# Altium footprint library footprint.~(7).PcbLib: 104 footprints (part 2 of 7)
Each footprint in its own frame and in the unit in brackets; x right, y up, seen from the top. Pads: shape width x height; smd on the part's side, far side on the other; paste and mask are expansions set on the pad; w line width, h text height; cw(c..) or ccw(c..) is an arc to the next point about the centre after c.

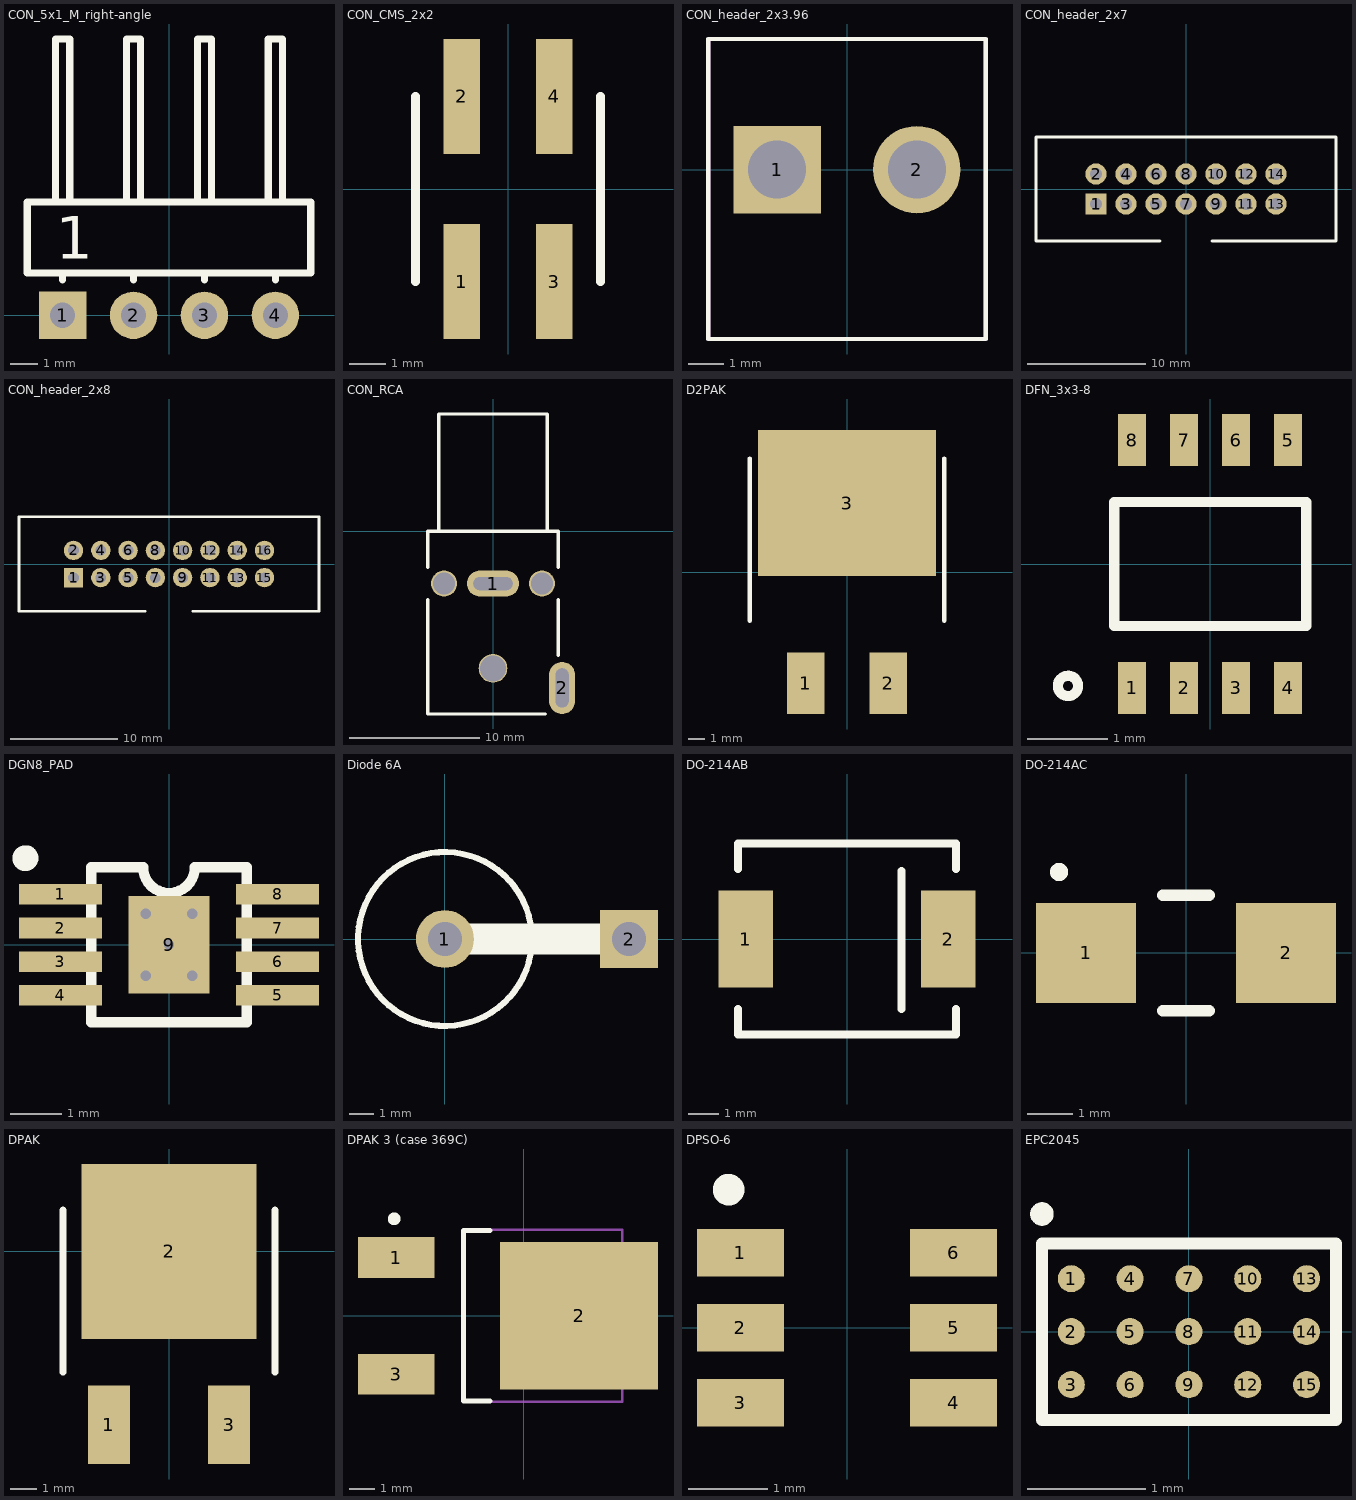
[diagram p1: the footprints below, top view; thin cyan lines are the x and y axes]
## CON_5x1_M_right-angle [mm] "step 2.54 TSW-104-22-G-S-RA"
height 2.41
pads (4):
  rect 1.7x1.7 hole 0.9: 1(-3.81,0)
  round 1.7 hole 0.9: 2(-1.27,0) 3(1.27,0) 4(3.81,0)
Top Overlay:
  lines w0.254: -4.064,4.06 -4.064,9.9 -3.556,9.9 -3.556,4.06 ; -3.81,1.27 -3.81,1.52 ; -1.524,4.06 -1.524,9.9 -1.016,9.9 -1.016,4.06 ; -1.27,1.27 -1.27,1.52 ; 1.016,4.06 1.016,9.9 1.524,9.9 1.524,4.06 ; 1.27,1.27 1.27,1.52 ; 3.556,4.06 3.556,9.9 4.064,9.9 4.064,4.06 ; 3.81,1.27 3.81,1.52 ; -5.08,1.52 5.08,1.52 5.08,4.06 -5.08,4.06 -5.08,1.52
  text "1" at -4.064,2.032 h1.52
3D body: height 2.41, standoff 0, extent -5.08,1.524 5.08,4.06
3D body: height 1.47, standoff 1.07, extent -4.191,-0.254 -3.429,9.906
3D body: height 1.47, standoff 1.07, extent -1.651,-0.254 -0.889,9.906
3D body: height 1.47, standoff 1.07, extent 0.889,-0.254 1.651,9.906
3D body: height 1.47, standoff 1.07, extent 3.429,-0.254 4.191,9.906

## CON_CMS_2x2 [mm] "2x2x2.54mm CMS"
height 9
pads (4):
  rect 1x3.15 smd: 1(-1.27,-2.54) 2(-1.27,2.54) 3(1.27,-2.54) 4(1.27,2.54)
Top Overlay:
  lines w0.254: -2.54,-2.54 -2.54,2.54 ; 2.54,-2.54 2.54,2.54
3D body: height 9.93, standoff 4.13, extent -1.59,0.95 -0.95,1.59
3D body: height 9.93, standoff 4.13, extent 0.95,0.95 1.59,1.59
3D body: height 9.93, standoff 4.13, extent 0.95,-1.59 1.59,-0.95
3D body: height 9.93, standoff 4.13, extent -1.59,-1.59 -0.95,-0.95
3D body: height 4.13, standoff 1.59, extent -2.54,-2.54 2.54,2.54

## CON_header_2x3.96 [mm] "2x3.96mm with lock"
height 10.7
pads (2):
  rect 2.475x2.475 hole 1.65: 1(-1.98,0)
  round 2.475 hole 1.65: 2(1.98,0)
Top Overlay:
  lines w0.127: -3.93,-4.8 -3.93,3.7 3.93,3.7 3.93,-4.8 -3.93,-4.8
Mechanical 4:
  lines w0.127: -3.93,-4.8 -3.93,3.7 ; -3.93,-4.8 3.93,-4.8 ; -3.93,-4.8 -3.93,3.7 ; -3.93,-4.8 3.93,-4.8 ; -3.93,3.7 3.93,3.7 ; -3.93,3.7 3.93,3.7 ; 3.93,-4.8 3.93,3.7 ; 3.93,-4.8 3.93,3.7
3D body: height 10.7, standoff 0, extent -3.93,-4.8 3.93,3.7

## CON_header_2x7 [mm] "2x7x2.54mm with lock"
height 9
pads (14):
  rect 1.8x1.8 hole 1: 1(-7.62,-1.27)
  round 1.8 hole 1: 2(-7.62,1.27) 3(-5.08,-1.27) 4(-5.08,1.27) 5(-2.54,-1.27) 6(-2.54,1.27) 7(0,-1.27) 8(0,1.27) 9(2.54,-1.27) 10(2.54,1.27) 11(5.08,-1.27) 12(5.08,1.27) 13(7.62,-1.27) 14(7.62,1.27)
Top Overlay:
  lines w0.254: -2.2,-4.4 -12.7,-4.4 -12.7,4.4 12.7,4.4 12.7,-4.4 2.2,-4.4
3D body: height 9, standoff 0, extent -12.7,-4.4 12.7,4.4

## CON_header_2x8 [mm] "2x8x2.54mm with lock"
height 9
pads (16):
  rect 1.8x1.8 hole 1: 1(-8.89,-1.27)
  round 1.8 hole 1: 2(-8.89,1.27) 3(-6.35,-1.27) 4(-6.35,1.27) 5(-3.81,-1.27) 6(-3.81,1.27) 7(-1.27,-1.27) 8(-1.27,1.27) 9(1.27,-1.27) 10(1.27,1.27) 11(3.81,-1.27) 12(3.81,1.27) 13(6.35,-1.27) 14(6.35,1.27) 15(8.89,-1.27) 16(8.89,1.27)
Top Overlay:
  lines w0.254: -2.2,-4.4 -13.97,-4.4 -13.97,4.4 13.97,4.4 13.97,-4.4 2.2,-4.4
3D body: height 9, standoff 0, extent -13.97,-4.4 13.97,4.4

## CON_RCA [mm] "JEITA RC-5231"
height 13
pads (5):
  oval 4x2 hole 1 slot 3 at 0 deg: 1(0,-4)
  oval 2x4 hole 1 slot 3 at 90 deg: 2(5.3,-12)
  round 2 hole 1.7: ""(-3.75,-4) ""(3.75,-4)
  round 2.2 hole 2: ""(0,-10.5)
Top Overlay:
  lines w0.254: -5,-5.25 -5,-14 4,-14 ; -5,-2.75 -5,0 5,0 5,-2.75 ; -4.15,0 -4.15,9 4.15,9 4.15,0 ; 5,-9.5 5,-5.25
3D body: height 13, standoff 0, extent -5,-14 5,0
3D body: height 10.65, standoff 2.35, extent -4.15,0 4.15,9

## D2PAK [mm] "D2PAK"
height 4.5
pads (3):
  rect 2.3x3.8 smd: 1(-2.54,-6.85) 2(2.54,-6.85)
  rect 11x9 smd: 3(0,4.25)
Top Overlay:
  lines w0.254: -6,-3 -6,7 ; 6,-3 6,7
3D body: height 2.38, standoff 0, extent -5.25,-3 5.25,7

## DFN_3x3-8 [mm] "DFN 3x3x0.9 - 8pin - 0.65pitch"
height 0.9
pads (8):
  rect 0.35x0.65 smd: 1(-0.975,-1.55) 2(-0.325,-1.55) 3(0.325,-1.55) 4(0.975,-1.55) 5(0.975,1.55) 6(0.325,1.55) 7(-0.325,1.55) 8(-0.975,1.55)
Top Overlay:
  circle w0.127: c-1.778,-1.524 r0.127
  lines w0.127: -1.2,-0.775 1.2,-0.775 1.2,0.775 -1.2,0.775 -1.2,-0.775
3D body: height 0.9, standoff 0, extent -1.5,-1.5 1.5,1.5

## DGN8_PAD [mm] "MSOP-PowerPAD; 8 Leads; Pitch 0.65 mm"
height 1.1
pads (9):
  rect 1.6x0.4 smd: 1(-2.1,0.975) 2(-2.1,0.325) 3(-2.1,-0.325) 4(-2.1,-0.975) 5(2.1,-0.975) 6(2.1,-0.325) 7(2.1,0.325) 8(2.1,0.975)
  rect 1.57x1.89 smd: 9(0,0)
via 0,0 diameter 0.4 hole 0.2
via -0.45,0.6 diameter 0.4 hole 0.2
via 0.45,0.6 diameter 0.4 hole 0.2
via 0.45,-0.6 diameter 0.4 hole 0.2
via -0.45,-0.6 diameter 0.4 hole 0.2
Top Overlay:
  circle w0.25: c-2.775,1.675 r0.125
  lines w0.2: -0.517,1.5 -1.5,1.5 -1.5,-1.5 1.5,-1.5 1.5,1.5 0.517,1.5 ; -0.5,1.5 ccw(c0,1.5) 0.5,1.5

## Diode 6A [mm] "diode 6A"
height 10
pads (2):
  round 2.4 hole 1.4: 1(0,0)
  rect 2.4x2.4 hole 1.4: 2(7.62,0)
Top Overlay:
  circle w0.254: c0,0 r3.6
  lines w1.3: 0,0 7.62,0

## DO-214AB [mil]
height 103.15
pads (2):
  rect 70x125 smd: 1(-130,0) 2(130,0)
Top Overlay:
  lines w10: -139.96,-90 -139.96,-122.44 139.96,-122.44 139.96,-90 ; -139.96,90 -139.96,122.44 139.96,122.44 139.96,90 ; 70,-90 70,87.17
3D body: height 103.15, standoff 0, extent -139.96,-122.44 139.96,122.44

## DO-214AC [mm]
height 2.3
pads (2):
  rect 2.2x2.2 smd: 1(-2.2,0) 2(2.2,0)
Top Overlay:
  circle w0.2: c-2.794,1.778 r0.1
  lines w0.254: -0.508,-1.27 0.508,-1.27 ; -0.508,1.27 0.508,1.27
3D body: height 2.3, standoff 0, extent -2.75,-1.4 2.75,1.4

## DPAK [mm] "DPAK"
height 2.38
pads (3):
  rect 1.6x3 smd: 1(-2.3,-6.65) 3(2.3,-6.65)
  rect 6.7x6.7 smd: 2(0,0)
Top Overlay:
  lines w0.254: -4.064,-4.634 -4.064,1.586 ; 4.064,-4.634 4.064,1.586
3D body: height 2.38, standoff 0, extent -3.365,-4.634 3.365,1.586

## DPAK 3 (case 369C) [mm] "D-PAK, 3-Pads, Body 6,21x6,73mm (max), IPC Medium Density"
height 2.38
pads (3):
  rect 3x1.6 smd: 1(-5,2.29) 3(-5,-2.29)
  rect 6.2x5.8 smd: 2(2.18,0)
Top Overlay:
  circle w0.25: c-5.08,3.81 r0.125
  lines w0.2: -1.32,-3.35 -2.35,-3.35 -2.35,3.35 -1.32,3.35
Mechanical 13:
  lines w0.1: -2.35,-3.375 3.87,-3.375 3.87,3.375 -2.35,3.375 -2.35,-3.375
3D body: height 2.38, standoff 0, extent -2.35,-3.375 3.87,3.375

## DPSO-6 [mm]
height 1.1
pads (6):
  rect 1.1x0.6 smd: 1(-1.35,0.95) 2(-1.35,0) 3(-1.35,-0.95) 4(1.35,-0.95) 5(1.35,0) 6(1.35,0.95)
Top Overlay:
  circle w0.2: c-1.5,1.75 r0.1
3D body: height 1.1, standoff 0, extent -0.9,-1.5 0.9,1.5

## EPC2045 [mm] "EPC2045 GaNFet"
height 0.685
pads (15):
  round 0.23 smd: 1(-1,0.45) 2(-1,0) 3(-1,-0.45) 4(-0.5,0.45) 5(-0.5,0) 6(-0.5,-0.45) 7(0,0.45) 8(0,0) 9(0,-0.45) 10(0.5,0.45) 11(0.5,0) 12(0.5,-0.45) 13(1,0.45) 14(1,0) 15(1,-0.45)
Top Overlay:
  circle w0.1: c-1.25,1 r0.05
  lines w0.1: -1.25,-0.75 -1.25,0.75 1.25,0.75 1.25,-0.75 -1.25,-0.75
3D body: height 0.68, standoff 0, extent -1.25,-0.75 1.25,0.75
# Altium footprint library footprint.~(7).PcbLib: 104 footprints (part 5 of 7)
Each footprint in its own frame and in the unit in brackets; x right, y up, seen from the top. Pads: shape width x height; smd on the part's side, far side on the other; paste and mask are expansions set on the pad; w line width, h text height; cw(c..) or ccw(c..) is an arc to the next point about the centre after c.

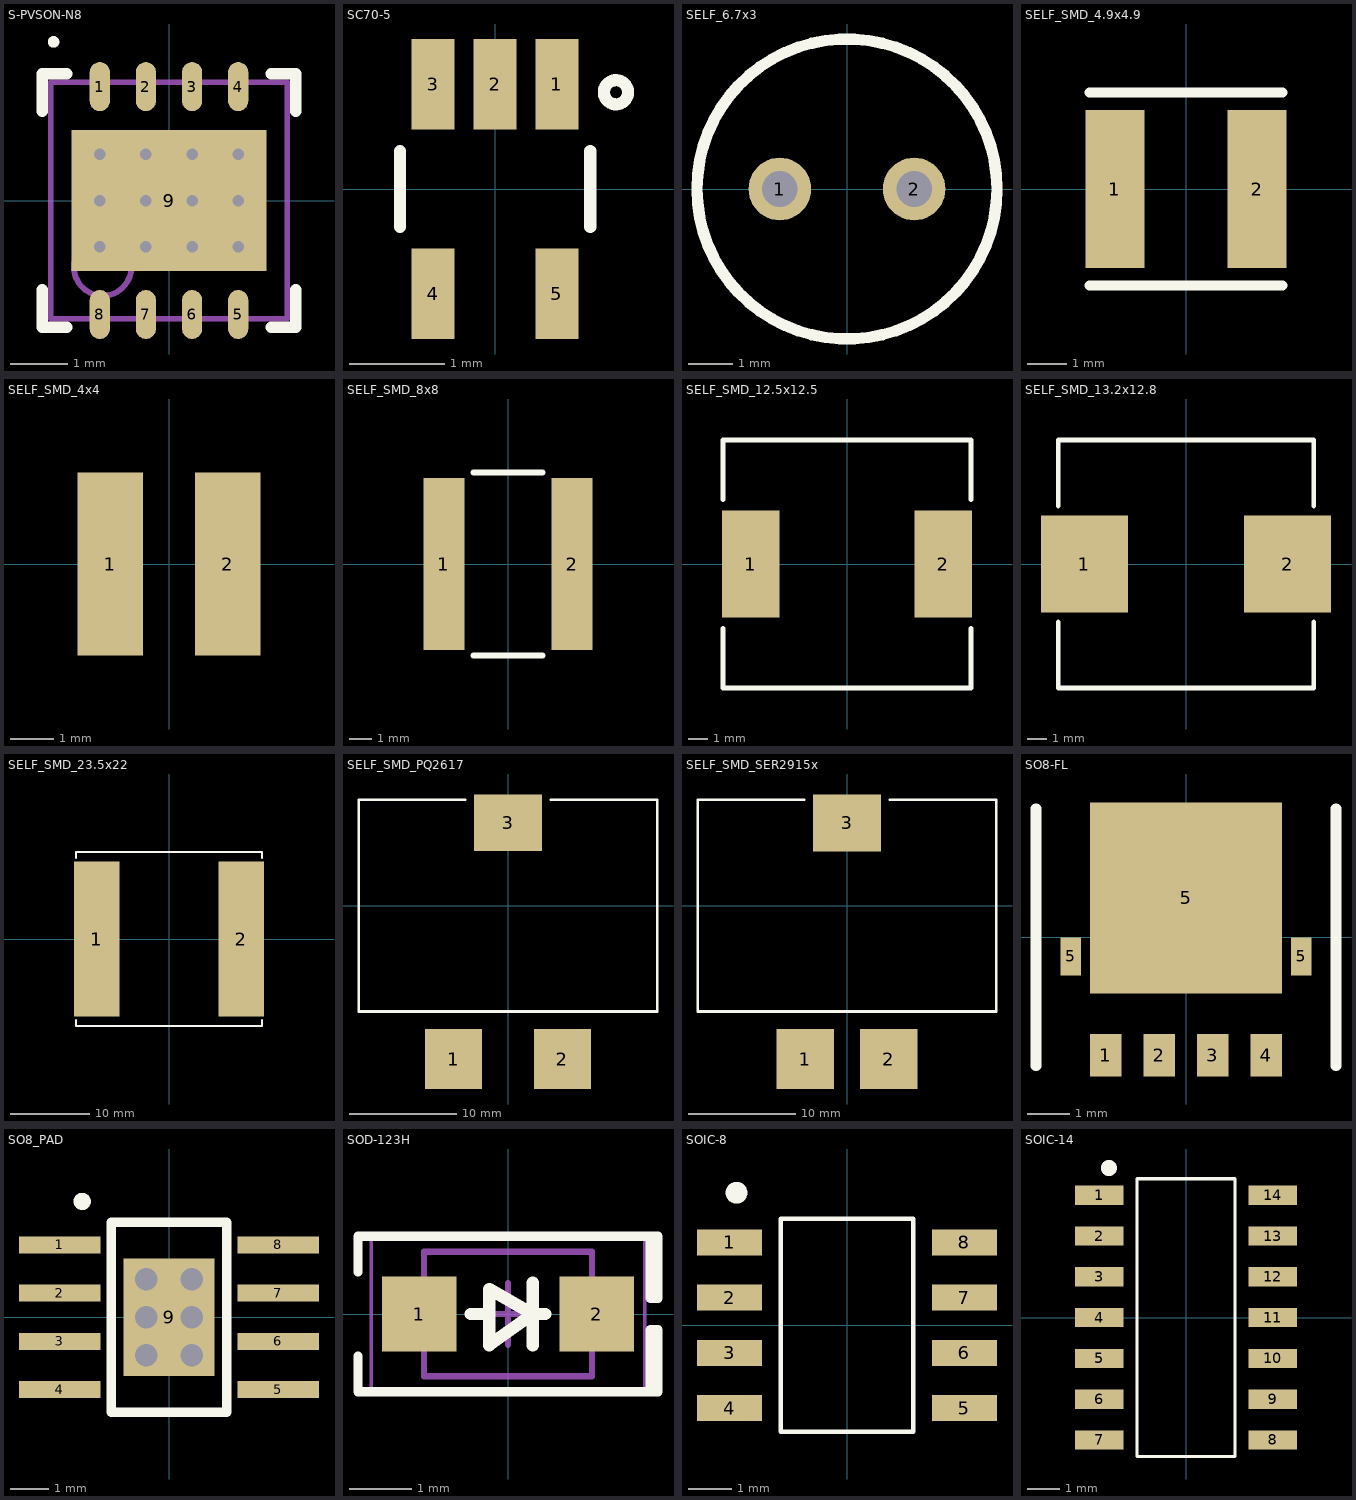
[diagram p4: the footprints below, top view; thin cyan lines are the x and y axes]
## S-PVSON-N8 [mm] "VSON, 8-Leads, Body 4,00x4,00mm, Pitch 0,80mm, Thermal Pad 3,38x2,45mm, IPC Medium Density"
height 1
pads (9):
  oval 0.35x0.85 smd: 1(-1.2,1.975) 2(-0.4,1.975) 3(0.4,1.975) 4(1.2,1.975) 5(1.2,-1.975) 6(0.4,-1.975) 7(-0.4,-1.975) 8(-1.2,-1.975)
  rect 3.38x2.45 smd paste-1.225: 9(0,0)
via -1.2,0 diameter 0.5 hole 0.2
via -1.2,0.8 diameter 0.5 hole 0.2
via -0.4,0.8 diameter 0.5 hole 0.2
via 0.4,0 diameter 0.5 hole 0.2
via 0.4,0.8 diameter 0.5 hole 0.2
via -0.4,0 diameter 0.5 hole 0.2
via 1.2,0.8 diameter 0.5 hole 0.2
via 1.2,0 diameter 0.5 hole 0.2
via 1.2,-0.8 diameter 0.5 hole 0.2
via 0.4,-0.8 diameter 0.5 hole 0.2
via -0.4,-0.8 diameter 0.5 hole 0.2
via -1.2,-0.8 diameter 0.5 hole 0.2
Top Overlay:
  circle w0.1: c-2,2.75 r0.05
  lines w0.2: -2.2,-1.545 -2.2,-2.2 -1.775,-2.2 ; -2.2,1.545 -2.2,2.2 -1.775,2.2 ; 1.775,-2.2 2.2,-2.2 2.2,-1.545 ; 1.775,2.2 2.2,2.2 2.2,1.545
Top Paste:
  rectangle: 0.15,0.15 1.65,1.15
  rectangle: 0.15,-1.15 1.65,-0.15
  rectangle: -1.65,-1.15 -0.15,-0.15
  rectangle: -1.65,0.15 -0.15,1.15
Mechanical 13:
  circle w0.1: c-1.15,-1.15 r0.5
  lines w0.1: -2.05,-2.05 2.05,-2.05 2.05,2.05 -2.05,2.05 -2.05,-2.05
3D body: height 1, standoff 0, extent -2.05,-2.05 2.05,2.05

## SC70-5 [mm] "SC70-5"
height 1.1
pads (5):
  rect 0.45x0.95 smd: 1(0.65,1.1) 2(0,1.1) 3(-0.65,1.1) 4(-0.65,-1.1) 5(0.65,-1.1)
Top Overlay:
  circle w0.127: c1.27,1.016 r0.127
  lines w0.127: -1,-0.4 -1,0.4 ; 1,-0.4 1,0.4
3D body: height 1.1, standoff 0, extent -1,-0.625 1,0.625

## SELF_6.7x3 [mm] "Inductor throug hole dia=6.7mm, H=10mm, spacing=3mm"
height 10
pads (2):
  round 1.4 hole 0.8: 1(-1.5,0) 2(1.5,0)
Top Overlay:
  circle w0.254: c0,0 r3.35
3D body: height 10, standoff 0, extent -3.35,-3.35 3.35,3.35

## SELF_SMD_4.9x4.9 [mm] "Self SMD 4.9x4.9mm"
height 3.1
pads (2):
  rect 1.5x4 smd: 1(-1.8,0) 2(1.8,0)
Top Overlay:
  lines w0.254: -2.45,-2.45 2.45,-2.45 ; -2.45,2.45 2.45,2.45
3D body: height 7.5, standoff 0, extent -2.45,-2.45 2.45,2.45

## SELF_SMD_4x4 [mm] "Self SMD 4x4mm"
height 1.2
pads (2):
  rect 1.5x4.2 smd: 1(-1.35,0) 2(1.35,0)
3D body: height 1.2, standoff 0, extent -2,-2 2,2

## SELF_SMD_8x8 [mm] "Self SMD 8x8mm"
height 3
pads (2):
  rect 1.8x7.5 smd: 1(-2.8,0) 2(2.8,0)
Top Overlay:
  lines w0.254: -1.5,-4 1.5,-4 ; -1.5,4 1.5,4
3D body: height 3, standoff 0, extent -4,-4 4,4

## SELF_SMD_12.5x12.5 [mm] "Self SMD 12.5x12.5mm"
height 7.5
pads (2):
  rect 2.9x5.4 smd: 1(-4.85,0) 2(4.85,0)
Top Overlay:
  lines w0.254: -6.25,-3.25 -6.25,-6.25 6.25,-6.25 6.25,-3.25 ; -6.25,3.25 -6.25,6.25 6.25,6.25 6.25,3.25
3D body: height 7.5, standoff 0, extent -6.25,-6.25 6.25,6.25

## SELF_SMD_13.2x12.8 [mm] "Self SMD 13.2x12.8mm"
height 6.2
pads (2):
  rect 4.5x5 smd: 1(-5.25,0) 2(5.25,0)
Top Overlay:
  lines w0.254: -6.6,-3 -6.6,-6.4 6.6,-6.4 6.6,-3 ; -6.6,3 -6.6,6.4 6.6,6.4 6.6,3
3D body: height 6.2, standoff 0, extent -6.6,-6.4 6.6,6.4

## SELF_SMD_23.5x22 [mm] "Self SMD 23.5x22mm"
height 12.6
pads (2):
  rect 5.75x19.6 smd: 1(-9.125,0) 2(9.125,0)
Top Overlay:
  lines w0.254: -11.75,-10.25 -11.75,-11 11.75,-11 11.75,-10.25 ; -11.75,10.25 -11.75,11 11.75,11 11.75,10.25
3D body: height 12.6, standoff 0, extent -11.75,-11 11.75,11

## SELF_SMD_PQ2617 [mil] "Bourns shielded power inductor PQ2617"
height 748.03
pads (3):
  rect 210x220 smd: 1(-200,-565) 2(200,-565)
  rect 250x208 smd: 3(0,304)
Top Overlay:
  lines w10: -157.48,389.76 -549.21,389.76 -549.21,-389.76 549.21,-389.76 549.21,389.76 157.48,389.76
3D body: height 393.7, standoff 196.85, extent -433.07,-432.94 433.08,432.95
3D body: height 748, standoff 0, extent -549.21,-389.76 549.21,389.76

## SELF_SMD_SER2915x [mm] "Coilcraft shielded power inductor SER2900"
height 15.36
pads (3):
  rect 5.4x5.6 smd: 1(-3.9,-14.36) 2(3.9,-14.36)
  rect 6.35x5.3 smd: 3(0,7.73)
Top Overlay:
  lines w0.254: -4,9.9 -13.95,9.9 -13.95,-9.9 13.95,-9.9 13.95,9.9 4,9.9
3D body: height 15.36, standoff 0, extent -13.95,-9.9 13.95,9.9
3D body: height 10, standoff 5, extent -11,-10.997 11,10.997

## SO8-FL [mm] "Power MOSFET"
height 1.1
pads (7):
  rect 0.75x1 smd: 1(-1.905,-2.795) 2(-0.635,-2.795) 3(0.635,-2.795) 4(1.905,-2.795)
  rect 0.495x0.905 smd: 5(-2.732,-0.453) 5(2.732,-0.453)
  rect 4.56x4.53 smd: 5(0,0.935)
Top Overlay:
  lines w0.254: -3.556,-3.048 -3.556,3.048 ; 3.556,-3.048 3.556,3.048
3D body: height 1, standoff 0, extent -2.45,-2.95 2.45,2.95

## SO8_PAD [mm] "SO8 with thermal pad"
height 1.7
pads (9):
  rect 2.15x0.45 smd: 1(-2.875,1.905) 2(-2.875,0.635) 3(-2.875,-0.635) 4(-2.875,-1.905) 5(2.875,-1.905) 6(2.875,-0.635) 7(2.875,0.635) 8(2.875,1.905)
  rect 2.4x3.1 smd: 9(0,0)
via -0.6,-1 diameter 1 hole 0.6
via 0.6,-1 diameter 1 hole 0.6
via -0.6,1 diameter 1 hole 0.6
via 0.6,1 diameter 1 hole 0.6
via -0.6,0 diameter 1 hole 0.6
via 0.6,0 diameter 1 hole 0.6
Top Overlay:
  circle w0.254: c-2.286,3.048 r0.1
  lines w0.254: -1.524,-2.5 -1.524,2.5 1.524,2.5 1.524,-2.5 -1.524,-2.5
3D body: height 1.7, standoff 0, extent -2,-2.5 2,2.5

## SOD-123H [mm] "SOD 123H, 2-Leads, Body 2x3.70mm, IPC Medium Density"
height 0.9
pads (2):
  rect 1.2x1.2 smd: 1(-1.43,0) 2(1.43,0)
Top Overlay:
  lines w0.15: -2.413,-0.675 -2.413,-1.25 2.413,-1.25 2.413,-1.016 2.413,-0.254 2.286,-0.254 2.286,-1.214 2.25,-1.25 ; -2.413,0.675 -2.413,1.25 2.286,1.25 ; 2.286,1.25 2.286,0.254 2.413,0.254 2.413,1.25 2.286,1.25
  lines w0.2: -0.6,0 -0.3,0 ; 0.4,-0.5 0.4,0.5 ; 0.6,0 0.4,0 ; 0.4,0 -0.3,0.4 -0.3,-0.5 0.4,0
Mechanical 13:
  lines w0.1: -1.35,-1 -1.35,1 1.35,1 1.35,-1 -1.35,-1
Mechanical 15:
  lines w0.05: -2.2,-1.25 -2.2,1.25 2.2,1.25 2.2,-1.25 -2.2,-1.25
  lines w0.1: -0.5,0 0.5,0 ; 0,-0.5 0,0.5
3D body "SOD123F.STEP": height 1.1, standoff 0, extent -1.75,-0.8 1.75,0.8

## SOIC-8 [mm] "8-Pin Plastic Narrow Body Small Outline Integrated Circuit 1.27 mm Pitch, IPC Medium Density"
height 1.75
pads (8):
  rect 1.5x0.6 smd: 1(-2.7,1.905) 2(-2.7,0.635) 3(-2.7,-0.635) 4(-2.7,-1.905) 5(2.7,-1.905) 6(2.7,-0.635) 7(2.7,0.635) 8(2.7,1.905)
Top Overlay:
  circle w0.25: c-2.54,3.048 r0.125
  lines w0.1: -1.524,-2.45 1.524,-2.45 1.524,2.45 -1.524,2.45 -1.524,-2.45
3D body: height 1.76, standoff 0, extent -1.95,-2.45 1.95,2.45

## SOIC-14 [mm] "14-Pin Plastic Narrow Body Small Outline Integrated Circuit 1.27 mm Pitch, IPC Medium Density"
height 1.76
pads (14):
  rect 1.5x0.6 smd: 1(-2.7,3.81) 2(-2.7,2.54) 3(-2.7,1.27) 4(-2.7,0) 5(-2.7,-1.27) 6(-2.7,-2.54) 7(-2.7,-3.81) 8(2.7,-3.81) 9(2.7,-2.54) 10(2.7,-1.27) 11(2.7,0) 12(2.7,1.27) 13(2.7,2.54) 14(2.7,3.81)
Top Overlay:
  circle w0.25: c-2.4,4.66 r0.125
  lines w0.1: -1.524,-4.325 1.524,-4.325 1.524,4.325 -1.524,4.325 -1.524,-4.325
3D body: height 1.76, standoff 0, extent -1.95,-4.325 1.95,4.325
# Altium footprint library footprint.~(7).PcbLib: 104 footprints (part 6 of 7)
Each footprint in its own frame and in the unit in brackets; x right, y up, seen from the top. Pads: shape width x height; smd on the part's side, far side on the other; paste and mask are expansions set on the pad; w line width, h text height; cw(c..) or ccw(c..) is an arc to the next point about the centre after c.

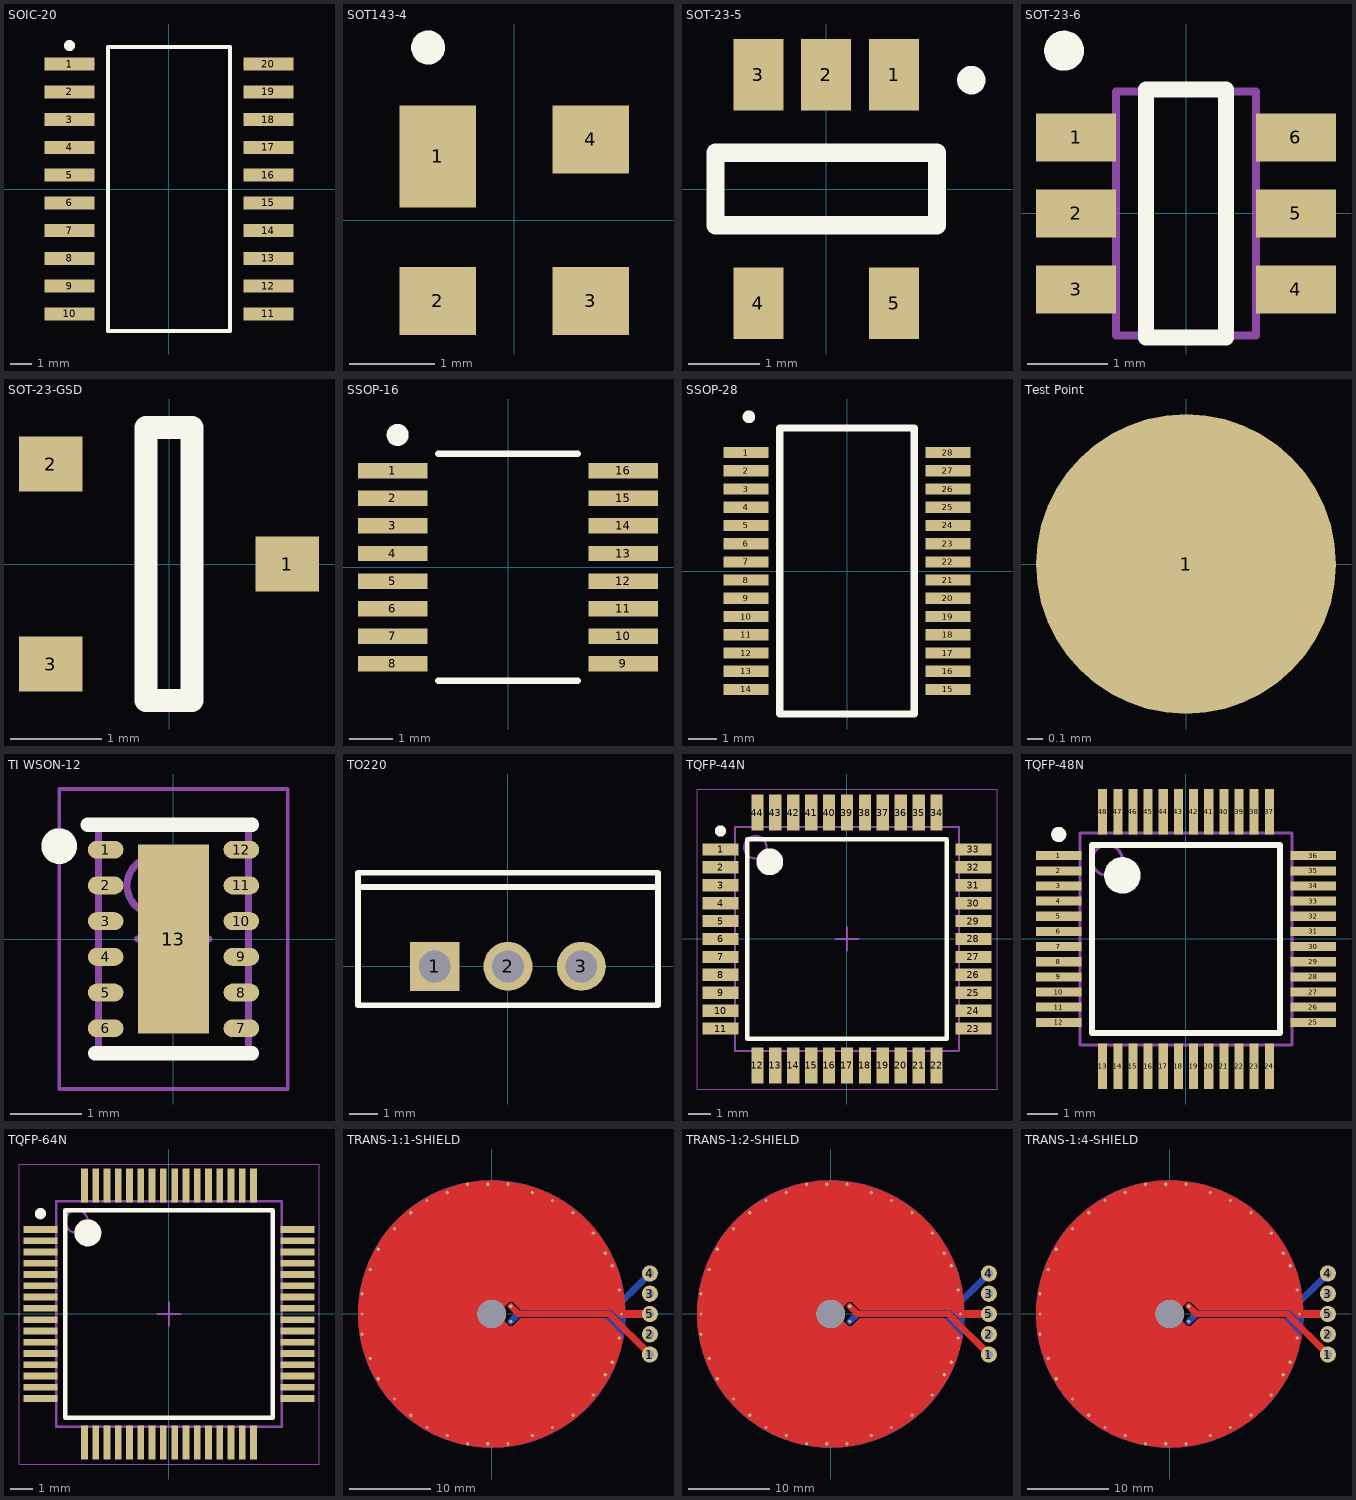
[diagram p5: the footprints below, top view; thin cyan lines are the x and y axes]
## SOIC-20 [mm] "20-Pin Plastic Wide Body Small Outline Integrated Circuit 1.27 mm Pitch, IPC Medium Density"
height 2.65
pads (20):
  rect 2.3x0.6 smd: 1(-4.55,5.715) 2(-4.55,4.445) 3(-4.55,3.175) 4(-4.55,1.905) 5(-4.55,0.635) 6(-4.55,-0.635) 7(-4.55,-1.905) 8(-4.55,-3.175) 9(-4.55,-4.445) 10(-4.55,-5.715) 11(4.55,-5.715) 12(4.55,-4.445) 13(4.55,-3.175) 14(4.55,-1.905) 15(4.55,-0.635) 16(4.55,0.635) 17(4.55,1.905) 18(4.55,3.175) 19(4.55,4.445) 20(4.55,5.715)
Top Overlay:
  circle w0.25: c-4.55,6.565 r0.125
  lines w0.2: -2.794,-6.5 -2.794,6.5 2.794,6.5 2.794,-6.5 -2.794,-6.5
3D body: height 2.65, standoff 0, extent -3.75,-6.4 3.75,6.4

## SOT143-4 [mm]
height 1.12
pads (4):
  rect 0.9x1.2 smd: 1(-0.9,0.75)
  rect 0.9x0.8 smd: 2(-0.9,-0.95) 3(0.9,-0.95) 4(0.9,0.95)
Top Overlay:
  circle w0.2: c-1.016,2.032 r0.1
3D body: height 1.12, standoff 0.1, extent -0.7,-1.52 0.7,1.52

## SOT-23-5 [mm] "SOT-23 5pins"
height 1.45
pads (5):
  rect 0.7x1 smd: 1(0.95,1.6) 2(0,1.6) 3(-0.95,1.6) 4(-0.95,-1.6) 5(0.95,-1.6)
Top Overlay:
  circle w0.2: c2.032,1.524 r0.1
  lines w0.254: -1.55,-0.508 1.55,-0.508 1.55,0.508 -1.55,0.508 -1.55,-0.508
3D body: height 1.45, standoff 0, extent -1.55,-0.9 1.55,0.9

## SOT-23-6 [mm] "SOT23, 6-Leads, Body 2,90x2,80mm, Pitch 0,95mm, IPC Medium Density"
height 1.1
pads (6):
  rect 1x0.6 smd: 1(-1.375,0.95) 2(-1.375,0) 3(-1.375,-0.95) 4(1.375,-0.95) 5(1.375,0) 6(1.375,0.95)
Top Overlay:
  circle w0.25: c-1.524,2.032 r0.125
  lines w0.2: -0.5,-1.55 -0.5,1.55 0.5,1.55 0.5,-1.55 -0.5,-1.55
Mechanical 13:
  lines w0.1: -0.875,-1.525 0.875,-1.525 0.875,1.525 -0.875,1.525 -0.875,-1.525
3D body: height 1.1, standoff 0, extent -0.875,-1.525 0.875,1.525

## SOT-23-GSD [mm] "Transistor"
height 1.1
pads (3):
  rect 0.7x0.6 smd: 1(1.3,0) 2(-1.3,1.1) 3(-1.3,-1.1)
Top Overlay:
  lines w0.254: -0.254,-1.5 -0.254,1.5 0.254,1.5 0.254,-1.5 -0.254,-1.5
3D body: height 1.1, standoff 0, extent -0.7,-1.5 0.7,1.5

## SSOP-16 [mil] "SSOP 16"
height 78.74
pads (16):
  rect 63x14 smd paste+0 mask+0: 1(-104.5,87.5) 2(-104.5,62.5) 3(-104.5,37.5) 4(-104.5,12.5) 5(-104.5,-12.5) 6(-104.5,-37.5) 7(-104.5,-62.5) 8(-104.5,-87.5) 9(104.5,-87.5) 10(104.5,-62.5) 11(104.5,-37.5) 12(104.5,-12.5) 13(104.5,12.5) 14(104.5,37.5) 15(104.5,62.5) 16(104.5,87.5)
Top Overlay:
  circle w10: c-100,120 r5
  lines w6: -63.03,-103 63.03,-103 ; -63.03,103 63.03,103
3D body "21-0055H_16-M.step": height 69.09, standoff 0, extent -122,-97.99 122.01,98

## SSOP-28 [mm]
height 2
pads (28):
  rect 1.6x0.4 smd: 1(-3.6,4.225) 2(-3.6,3.575) 3(-3.6,2.925) 4(-3.6,2.275) 5(-3.6,1.625) 6(-3.6,0.975) 7(-3.6,0.325) 8(-3.6,-0.325) 9(-3.6,-0.975) 10(-3.6,-1.625) 11(-3.6,-2.275) 12(-3.6,-2.925) 13(-3.6,-3.575) 14(-3.6,-4.225) 15(3.6,-4.225) 16(3.6,-3.575) 17(3.6,-2.925) 18(3.6,-2.275) 19(3.6,-1.625) 20(3.6,-0.975) 21(3.6,-0.325) 22(3.6,0.325) 23(3.6,0.975) 24(3.6,1.625) 25(3.6,2.275) 26(3.6,2.925) 27(3.6,3.575) 28(3.6,4.225)
Top Overlay:
  circle w0.254: c-3.5,5.5 r0.1
  lines w0.254: -2.4,-5.1 2.4,-5.1 2.4,5.1 -2.4,5.1 -2.4,-5.1
3D body: height 2, standoff 0, extent -2.65,-5.1 2.65,5.1

## Test Point [mm] "Test Point"
pads (1):
  round 2 smd: 1(0,0)

## TI WSON-12 [mm] "WSON, 12-Leads, Body 2.00x3.00mm, Pitch 0.50mm, Thermal Pad 1x2.65mm, IPC Medium Density"
height 0.8
pads (13):
  oval 0.5x0.25 smd: 1(-0.95,1.25) 2(-0.95,0.75) 3(-0.95,0.25) 4(-0.95,-0.25) 5(-0.95,-0.75) 6(-0.95,-1.25) 7(0.95,-1.25) 8(0.95,-0.75) 9(0.95,-0.25) 10(0.95,0.25) 11(0.95,0.75) 12(0.95,1.25)
  rect 1x2.65 smd: 13(0,0)
Top Overlay:
  circle w0.25: c-1.6,1.3 r0.125
  lines w0.2: -1.2,1.6 1.1,1.6 ; -1.1,-1.6 1.1,-1.6
Mechanical 13:
  circle w0.1: c-0.25,0.75 r0.4
  lines w0.1: -1.05,-1.55 1.05,-1.55 1.05,1.55 -1.05,1.55 -1.05,-1.55
Mechanical 15:
  lines w0.05: -1.6,-2.1 1.6,-2.1 1.6,2.1 -1.6,2.1 -1.6,-2.1
  lines w0.1: -0.5,0 0.5,0 ; 0,-0.5 0,0.5
3D body: height 0.8, standoff 0.08, extent -1.05,-1.55 1.05,1.55

## TO220 [mm] "SIP; 3 Leads; Body 16 x 10.2 x 4.5 mm (typ); Pitch 2.54 mm"
height 19.7
pads (3):
  rect 1.7x1.7 hole 1.1: 1(-2.54,0)
  round 1.7 hole 1.1: 2(0,0) 3(2.54,0)
Top Overlay:
  lines w0.2: -5.2,2.75 5.2,2.75 ; -5.2,-1.35 -5.2,3.25 5.2,3.25 5.2,-1.35 -5.2,-1.35

## TQFP-44N [mm] "TQFP, 44-Leads, Body 10,00x10,00mm, Pitch 0,80mm, IPC Medium Density"
height 1.2
pads (44):
  rect 1.6x0.55 smd: 1(-5.65,4) 2(-5.65,3.2) 3(-5.65,2.4) 4(-5.65,1.6) 5(-5.65,0.8) 6(-5.65,0) 7(-5.65,-0.8) 8(-5.65,-1.6) 9(-5.65,-2.4) 10(-5.65,-3.2) 11(-5.65,-4) 23(5.65,-4) 24(5.65,-3.2) 25(5.65,-2.4) 26(5.65,-1.6) 27(5.65,-0.8) 28(5.65,0) 29(5.65,0.8) 30(5.65,1.6) 31(5.65,2.4) 32(5.65,3.2) 33(5.65,4)
  rect 0.55x1.6 smd: 12(-4,-5.65) 13(-3.2,-5.65) 14(-2.4,-5.65) 15(-1.6,-5.65) 16(-0.8,-5.65) 17(0,-5.65) 18(0.8,-5.65) 19(1.6,-5.65) 20(2.4,-5.65) 21(3.2,-5.65) 22(4,-5.65) 34(4,5.65) 35(3.2,5.65) 36(2.4,5.65) 37(1.6,5.65) 38(0.8,5.65) 39(0,5.65) 40(-0.8,5.65) 41(-1.6,5.65) 42(-2.4,5.65) 43(-3.2,5.65) 44(-4,5.65)
Top Overlay:
  circle w0.25: c-5.65,4.825 r0.125
  circle w0.6: c-3.45,3.45 r0.3
  lines w0.2: -4.45,-4.45 -4.45,4.45 4.45,4.45 4.45,-4.45 -4.45,-4.45
Mechanical 13:
  circle w0.1: c-4.1,4.1 r0.5
  lines w0.1: -5,-5 -5,5 5,5 5,-5 -5,-5
Mechanical 15:
  lines w0.05: -6.7,-6.7 -6.7,6.7 6.7,6.7 6.7,-6.7 -6.7,-6.7
  lines w0.1: -0.5,0 0.5,0 ; 0,-0.5 0,0.5
3D body: height 1.2, standoff 0.05, extent -5,-5 5,5

## TQFP-48N [mm] "TSQFP, 48-Leads, Body 7,00x7,00mm, Pitch 0,50mm, IPC Medium Density"
height 1.2
pads (48):
  rect 1.5x0.3 smd: 1(-4.2,2.75) 2(-4.2,2.25) 3(-4.2,1.75) 4(-4.2,1.25) 5(-4.2,0.75) 6(-4.2,0.25) 7(-4.2,-0.25) 8(-4.2,-0.75) 9(-4.2,-1.25) 10(-4.2,-1.75) 11(-4.2,-2.25) 12(-4.2,-2.75) 25(4.2,-2.75) 26(4.2,-2.25) 27(4.2,-1.75) 28(4.2,-1.25) 29(4.2,-0.75) 30(4.2,-0.25) 31(4.2,0.25) 32(4.2,0.75) 33(4.2,1.25) 34(4.2,1.75) 35(4.2,2.25) 36(4.2,2.75)
  rect 0.3x1.5 smd: 13(-2.75,-4.2) 14(-2.25,-4.2) 15(-1.75,-4.2) 16(-1.25,-4.2) 17(-0.75,-4.2) 18(-0.25,-4.2) 19(0.25,-4.2) 20(0.75,-4.2) 21(1.25,-4.2) 22(1.75,-4.2) 23(2.25,-4.2) 24(2.75,-4.2) 37(2.75,4.2) 38(2.25,4.2) 39(1.75,4.2) 40(1.25,4.2) 41(0.75,4.2) 42(0.25,4.2) 43(-0.25,4.2) 44(-0.75,4.2) 45(-1.25,4.2) 46(-1.75,4.2) 47(-2.25,4.2) 48(-2.75,4.2)
Top Overlay:
  circle w0.25: c-4.2,3.45 r0.125
  circle w0.6: c-2.1,2.1 r0.3
  lines w0.2: -3.1,-3.1 -3.1,3.1 3.1,3.1 3.1,-3.1 -3.1,-3.1
Mechanical 13:
  circle w0.1: c-2.6,2.6 r0.5
  lines w0.1: -3.5,-3.5 -3.5,3.5 3.5,3.5 3.5,-3.5 -3.5,-3.5
3D body: height 1.2, standoff 0.05, extent -3.5,-3.5 3.5,3.5

## TQFP-64N [mm] "TSQFP, 64-Leads, Body 10,00x10,00mm, Pitch 0,50mm, IPC Medium Density"
height 1.2
pads (64):
  rect 1.5x0.3 smd: 1(-5.7,3.75) 2(-5.7,3.25) 3(-5.7,2.75) 4(-5.7,2.25) 5(-5.7,1.75) 6(-5.7,1.25) 7(-5.7,0.75) 8(-5.7,0.25) 9(-5.7,-0.25) 10(-5.7,-0.75) 11(-5.7,-1.25) 12(-5.7,-1.75) 13(-5.7,-2.25) 14(-5.7,-2.75) 15(-5.7,-3.25) 16(-5.7,-3.75) 33(5.7,-3.75) 34(5.7,-3.25) 35(5.7,-2.75) 36(5.7,-2.25) 37(5.7,-1.75) 38(5.7,-1.25) 39(5.7,-0.75) 40(5.7,-0.25) 41(5.7,0.25) 42(5.7,0.75) 43(5.7,1.25) 44(5.7,1.75) 45(5.7,2.25) 46(5.7,2.75) 47(5.7,3.25) 48(5.7,3.75)
  rect 0.3x1.5 smd: 17(-3.75,-5.7) 18(-3.25,-5.7) 19(-2.75,-5.7) 20(-2.25,-5.7) 21(-1.75,-5.7) 22(-1.25,-5.7) 23(-0.75,-5.7) 24(-0.25,-5.7) 25(0.25,-5.7) 26(0.75,-5.7) 27(1.25,-5.7) 28(1.75,-5.7) 29(2.25,-5.7) 30(2.75,-5.7) 31(3.25,-5.7) 32(3.75,-5.7) 49(3.75,5.7) 50(3.25,5.7) 51(2.75,5.7) 52(2.25,5.7) 53(1.75,5.7) 54(1.25,5.7) 55(0.75,5.7) 56(0.25,5.7) 57(-0.25,5.7) 58(-0.75,5.7) 59(-1.25,5.7) 60(-1.75,5.7) 61(-2.25,5.7) 62(-2.75,5.7) 63(-3.25,5.7) 64(-3.75,5.7)
Top Overlay:
  circle w0.25: c-5.7,4.45 r0.125
  circle w0.6: c-3.6,3.6 r0.3
  lines w0.2: -4.6,-4.6 -4.6,4.6 4.6,4.6 4.6,-4.6 -4.6,-4.6
Mechanical 13:
  circle w0.1: c-4.1,4.1 r0.5
  lines w0.1: -5,-5 -5,5 5,5 5,-5 -5,-5
Mechanical 15:
  lines w0.05: -6.65,-6.65 -6.65,6.65 6.65,6.65 6.65,-6.65 -6.65,-6.65
  lines w0.1: -0.5,0 0.5,0 ; 0,-0.5 0,0.5
3D body: height 1.2, standoff 0.05, extent -5,-5 5,5

## TRANS-1:1-SHIELD [mm] "PCB trace transformer, 1:1, shielded, 1A, 1µH, 500mOhm"
pads (5):
  round 2 hole 1: 1(19.5,-5) 2(19.5,-2.5) 3(19.5,2.5) 4(19.5,5) 5(19.5,0)
via 16,0 diameter 0.4 hole 0.2
via 15.726,2.949 diameter 0.4 hole 0.2
via -16,0 diameter 0.4 hole 0.2
via 15.726,-2.949 diameter 0.4 hole 0.2
via 14.856,5.942 diameter 0.4 hole 0.2
via 14.856,-5.942 diameter 0.4 hole 0.2
via -5.5,15 diameter 0.4 hole 0.2
via -5.5,-15 diameter 0.4 hole 0.2
via -0.5,16 diameter 0.4 hole 0.2
via -0.5,-16 diameter 0.4 hole 0.2
via 14,-7.5 diameter 0.4 hole 0.2
via 14,7.5 diameter 0.4 hole 0.2
via 12.5,10 diameter 0.4 hole 0.2
via 12.5,-10 diameter 0.4 hole 0.2
via 10,-12.5 diameter 0.4 hole 0.2
via 10,12.5 diameter 0.4 hole 0.2
via 7.5,14 diameter 0.4 hole 0.2
via 7.5,-14 diameter 0.4 hole 0.2
via 5,15 diameter 0.4 hole 0.2
via 2,16 diameter 0.4 hole 0.2
via -3,16 diameter 0.4 hole 0.2
via 5,-15 diameter 0.4 hole 0.2
via -8,-14 diameter 0.4 hole 0.2
via -8,14 diameter 0.4 hole 0.2
via -10,12.5 diameter 0.4 hole 0.2
via -10,-12.5 diameter 0.4 hole 0.2
via -12,-10.5 diameter 0.4 hole 0.2
via -12,10.5 diameter 0.4 hole 0.2
via -14,8 diameter 0.4 hole 0.2
via -14,-8 diameter 0.4 hole 0.2
via -15,-5.5 diameter 0.4 hole 0.2
via -15,5.5 diameter 0.4 hole 0.2
via -16,2.5 diameter 0.4 hole 0.2
via -16,-2.5 diameter 0.4 hole 0.2
via 0,0 diameter 3.5 hole 3.5
via 2,-16 diameter 0.4 hole 0.2
via -3,-16 diameter 0.4 hole 0.2
via 2.35,-0.938 diameter 0.4 hole 0.2
via 2.346,0.949 diameter 0.4 hole 0.2
Top Layer:
  region: 0,0 2,-2 2.5,-2 3.5,-1 13.777,-1 15.726,-2.949 15.614,-3.548 15.298,-4.727 14.894,-5.878 14.403,-6.995 13.828,-8.072 13.173,-9.101 12.442,-10.078 11.639,-10.996 10.767,-11.85 9.834,-12.636 8.843,-13.348 7.801,-13.983 6.713,-14.536 5.587,-15.005 4.428,-15.387 3.244,-15.68 2.04,-15.881 0.825,-15.99 -0.395,-16.007 -1.613,-15.93 -2.821,-15.761 -4.013,-15.501 -5.182,-15.15 -6.321,-14.711 -7.422,-14.187 -8.481,-13.581 -9.491,-12.896 -10.445,-12.135 -11.339,-11.305 -12.167,-10.409 -12.924,-9.452 -13.606,-8.44 -14.21,-7.38 -14.73,-6.276 -15.165,-5.136 -15.513,-3.966 -15.77,-2.774 -15.935,-1.565 -16.008,-0.347 -15.988,0.873 -15.875,2.088 -15.67,3.291 -15.374,4.475 -14.988,5.632 -14.516,6.757 -13.959,7.843 -13.321,8.883 -12.606,9.872 -11.818,10.803 -10.961,11.672 -10.04,12.473 -9.061,13.201 -8.03,13.853 -6.952,14.424 -5.833,14.911 -4.681,15.312 -3.501,15.624 -2.301,15.845 -1.088,15.975 0.132,16.011 1.351,15.955 2.562,15.805 3.758,15.564 4.932,15.233 6.078,14.813 7.188,14.307 8.257,13.719 9.277,13.05 10.244,12.306 11.151,11.49 11.994,10.607 12.767,9.663 13.466,8.663 14.086,7.612 14.625,6.518 15.079,5.385 15.445,4.221 15.722,3.033 15.907,1.827 16,0.61 16,0 15,1 3.5,1 2.5,2 2,2
  lines w0.254: 0,-1 1,-1
  lines w0.8: 2.346,0.949 3.295,0 14.5,0 19.5,-5
  lines w1: -1,0 0,1 ; 19.5,0 16,0 ; 16,0 ccw(c0,0) 15.726,-2.949 13.777,-1 3.75,-1 2.75,-2 2,-2 0,0 2,2 2.75,2 3.75,1 15,1 16,0
Mid-Layer 1:
  lines w0.8: 2.346,0.949 ccw(c-0.5,0) -3.5,0 ccw(c0,0) 3.5,0 ccw(c-0.5,0) -4.5,0 ccw(c0,0) 4.5,0 ccw(c-0.5,0) -5.5,0 ccw(c0,0) 5.5,0 ccw(c-0.5,0) -6.5,0 ccw(c0,0) 6.5,0 ccw(c-0.5,0) -7.5,0 ccw(c0,0) 7.5,0 ccw(c-0.5,0) -8.5,0 ccw(c0,0) 8.5,0 ccw(c-0.5,0) -9.5,0 ccw(c0,0) 9.5,0 ccw(c-0.5,0) -10.5,0 ccw(c0,0) 10.5,0 ccw(c-0.5,0) -11.5,0 ccw(c0,0) 11.5,0 ccw(c-0.5,0) -12.5,0 ccw(c0,0) 12.5,0 ccw(c-0.5,0) -13.5,0 ccw(c0,0) 13.5,0 ccw(c-0.5,0) -14.5,0 ccw(c0,0) 14.423,-1.492 ; 14.5,-1.5 18.5,-1.5 19.5,-2.5
  lines w1: 15.726,-2.949 cw(c0,0) 16,0 19.5,0
Mid-Layer 2:
  lines w0.8: 2.35,-0.938 cw(c-0.5,0) -3.5,0 cw(c0,0) 3.5,0 cw(c-0.5,0) -4.5,0 cw(c0,0) 4.5,0 cw(c-0.5,0) -5.5,0 cw(c0,0) 5.5,0 cw(c-0.5,0) -6.5,0 cw(c0,0) 6.5,0 cw(c-0.5,0) -7.5,0 cw(c0,0) 7.5,0 cw(c-0.5,0) -8.5,0 cw(c0,0) 8.5,0 cw(c-0.5,0) -9.5,0 cw(c0,0) 9.5,0 cw(c-0.5,0) -10.5,0 cw(c0,0) 10.5,0 cw(c-0.5,0) -11.5,0 cw(c0,0) 11.5,0 cw(c-0.5,0) -12.5,0 cw(c0,0) 12.5,0 cw(c-0.5,0) -13.5,0 cw(c0,0) 13.5,0 cw(c-0.5,0) -14.5,0 cw(c0,0) 14.422,1.5 18.5,1.5 19.5,2.5
  lines w1: 15.726,2.949 ccw(c0,0) 16,0 19.5,0
Bottom Layer:
  region: 183 vertices and 0 holes, not listed, extent -16.508,-16.512 16.5,16.507
  region: 0,0 2,-2 2.5,-2 3.5,-1 15,-1 16,0 16,-0.61 15.907,-1.827 15.722,-3.033 15.445,-4.221 15.079,-5.385 14.625,-6.518 14.086,-7.612 13.466,-8.663 12.767,-9.663 11.994,-10.607 11.151,-11.49 10.244,-12.306 9.277,-13.05 8.257,-13.719 7.188,-14.307 6.078,-14.813 4.932,-15.233 3.758,-15.564 2.562,-15.805 1.351,-15.955 0.132,-16.011 -1.088,-15.975 -2.301,-15.845 -3.501,-15.624 -4.681,-15.312 -5.833,-14.911 -6.952,-14.424 -8.03,-13.853 -9.061,-13.201 -10.04,-12.473 -10.961,-11.672 -11.818,-10.803 -12.606,-9.872 -13.321,-8.883 -13.959,-7.843 -14.516,-6.757 -14.988,-5.632 -15.374,-4.475 -15.67,-3.291 -15.875,-2.088 -15.988,-0.873 -16.008,0.347 -15.935,1.565 -15.77,2.774 -15.513,3.966 -15.165,5.136 -14.73,6.276 -14.21,7.38 -13.606,8.44 -12.924,9.452 -12.167,10.409 -11.339,11.305 -10.445,12.135 -9.491,12.896 -8.481,13.581 -7.422,14.187 -6.321,14.711 -5.182,15.15 -4.013,15.501 -2.821,15.761 -1.613,15.93 -0.395,16.007 0.825,15.99 2.04,15.881 3.244,15.68 4.428,15.387 5.587,15.005 6.713,14.536 7.801,13.983 8.843,13.348 9.834,12.636 10.767,11.85 11.639,10.996 12.442,10.078 13.173,9.101 13.828,8.072 14.403,6.995 14.894,5.878 15.298,4.727 15.614,3.548 15.726,2.949 13.777,1 3.5,1 2.5,2 2,2
  lines w0.8: 2.35,-0.938 3.287,0 14.5,0 19.5,5
  lines w1: -1,0 0,-1 ; 19.5,0 16,0 ; 16,0 cw(c0,0) 15.726,2.949 13.777,1 3.75,1 2.75,2 2,2 0,0 2,-2 2.75,-2 3.75,-1 15,-1 16,0

## TRANS-1:2-SHIELD [mm] "PCB trace transformer, 1:2, shielded, 1A, 1µH, 500mOhm"
pads (5):
  round 2 hole 1: 1(19.5,-5) 2(19.5,-2.5) 3(19.5,2.5) 4(19.5,5) 5(19.5,0)
via 2.346,0.949 diameter 0.4 hole 0.2
via 2.35,-0.938 diameter 0.4 hole 0.2
via 16,0 diameter 0.4 hole 0.2
via 15.726,2.949 diameter 0.4 hole 0.2
via -16,0 diameter 0.4 hole 0.2
via 15.726,-2.949 diameter 0.4 hole 0.2
via 14.856,5.942 diameter 0.4 hole 0.2
via 14.856,-5.942 diameter 0.4 hole 0.2
via -5.5,15 diameter 0.4 hole 0.2
via -5.5,-15 diameter 0.4 hole 0.2
via -0.5,16 diameter 0.4 hole 0.2
via -0.5,-16 diameter 0.4 hole 0.2
via 14,-7.5 diameter 0.4 hole 0.2
via 14,7.5 diameter 0.4 hole 0.2
via 12.5,10 diameter 0.4 hole 0.2
via 12.5,-10 diameter 0.4 hole 0.2
via 10,-12.5 diameter 0.4 hole 0.2
via 10,12.5 diameter 0.4 hole 0.2
via 7.5,14 diameter 0.4 hole 0.2
via 7.5,-14 diameter 0.4 hole 0.2
via 5,15 diameter 0.4 hole 0.2
via 2,16 diameter 0.4 hole 0.2
via -3,16 diameter 0.4 hole 0.2
via 5,-15 diameter 0.4 hole 0.2
via -8,-14 diameter 0.4 hole 0.2
via -8,14 diameter 0.4 hole 0.2
via -10,12.5 diameter 0.4 hole 0.2
via -10,-12.5 diameter 0.4 hole 0.2
via -12,-10.5 diameter 0.4 hole 0.2
via -12,10.5 diameter 0.4 hole 0.2
via -14,8 diameter 0.4 hole 0.2
via -14,-8 diameter 0.4 hole 0.2
via -15,-5.5 diameter 0.4 hole 0.2
via -15,5.5 diameter 0.4 hole 0.2
via -16,2.5 diameter 0.4 hole 0.2
via -16,-2.5 diameter 0.4 hole 0.2
via 0,0 diameter 3.5 hole 3.5
via 2,-16 diameter 0.4 hole 0.2
via -3,-16 diameter 0.4 hole 0.2
Top Layer:
  region: 0,0 2,-2 2.5,-2 3.5,-1 13.777,-1 15.726,-2.949 15.614,-3.548 15.298,-4.727 14.894,-5.878 14.403,-6.995 13.828,-8.072 13.173,-9.101 12.442,-10.078 11.639,-10.996 10.767,-11.85 9.834,-12.636 8.843,-13.348 7.801,-13.983 6.713,-14.536 5.587,-15.005 4.428,-15.387 3.244,-15.68 2.04,-15.881 0.825,-15.99 -0.395,-16.007 -1.613,-15.93 -2.821,-15.761 -4.013,-15.501 -5.182,-15.15 -6.321,-14.711 -7.422,-14.187 -8.481,-13.581 -9.491,-12.896 -10.445,-12.135 -11.339,-11.305 -12.167,-10.409 -12.924,-9.452 -13.606,-8.44 -14.21,-7.38 -14.73,-6.276 -15.165,-5.136 -15.513,-3.966 -15.77,-2.774 -15.935,-1.565 -16.008,-0.347 -15.988,0.873 -15.875,2.088 -15.67,3.291 -15.374,4.475 -14.988,5.632 -14.516,6.757 -13.959,7.843 -13.321,8.883 -12.606,9.872 -11.818,10.803 -10.961,11.672 -10.04,12.473 -9.061,13.201 -8.03,13.853 -6.952,14.424 -5.833,14.911 -4.681,15.312 -3.501,15.624 -2.301,15.845 -1.088,15.975 0.132,16.011 1.351,15.955 2.562,15.805 3.758,15.564 4.932,15.233 6.078,14.813 7.188,14.307 8.257,13.719 9.277,13.05 10.244,12.306 11.151,11.49 11.994,10.607 12.767,9.663 13.466,8.663 14.086,7.612 14.625,6.518 15.079,5.385 15.445,4.221 15.722,3.033 15.907,1.827 16,0.61 16,0 15,1 3.5,1 2.5,2 2,2
  lines w0.254: 0,-1 1,-1
  lines w0.8: 2.346,0.949 3.295,0 14.5,0 19.5,-5
  lines w1: -1,0 0,1 ; 19.5,0 16,0 ; 16,0 ccw(c0,0) 15.726,-2.949 13.777,-1 3.75,-1 2.75,-2 2,-2 0,0 2,2 2.75,2 3.75,1 15,1 16,0
Mid-Layer 1:
  lines w0.8: 2.346,0.949 ccw(c-0.5,0) -3.5,0 ccw(c0,0) 3.5,0 ccw(c-0.5,0) -4.5,0 ccw(c0,0) 4.5,0 ccw(c-0.5,0) -5.5,0 ccw(c0,0) 5.5,0 ccw(c-0.5,0) -6.5,0 ccw(c0,0) 6.5,0 ccw(c-0.5,0) -7.5,0 ccw(c0,0) 7.5,0 ccw(c-0.5,0) -8.5,0 ccw(c0,0) 8.5,0 ccw(c-0.5,0) -9.5,0 ccw(c0,0) 9.5,0 ccw(c-0.5,0) -10.5,0 ccw(c0,0) 10.5,0 ccw(c-0.5,0) -11.5,0 ccw(c0,0) 11.5,0 ccw(c-0.5,0) -12.5,0 ccw(c0,0) 12.5,0 ccw(c-0.5,0) -13.5,0 ccw(c0,0) 13.5,0 ccw(c-0.5,0) -14.5,0 ccw(c0,0) 14.423,-1.492 ; 14.5,-1.5 18.5,-1.5 19.5,-2.5
  lines w1: 15.726,-2.949 cw(c0,0) 16,0 19.5,0
Mid-Layer 2:
  lines w0.3: 2.35,-0.938 cw(c-0.5,0) -3.5,0 cw(c0,0) 3.5,0 cw(c-0.25,0) -4,0 cw(c0,0) 4,0 cw(c-0.25,0) -4.5,0 cw(c0,0) 4.5,0 cw(c-0.25,0) -5,0 cw(c0,0) 5,0 cw(c-0.25,0) -5.5,0 cw(c0,0) 5.5,0 cw(c-0.25,0) -6,0 cw(c0,0) 6,0 cw(c-0.25,0) -6.5,0 cw(c0,0) 6.5,0 cw(c-0.25,0) -7,0 cw(c0,0) 7,0 cw(c-0.25,0) -7.5,0 cw(c0,0) 7.5,0 cw(c-0.25,0) -8,0 cw(c0,0) 8,0 cw(c-0.25,0) -8.5,0 cw(c0,0) 8.5,0 cw(c-0.25,0) -9,0 cw(c0,0) 9,0 cw(c-0.25,0) -9.5,0 cw(c0,0) 9.5,0 cw(c-0.25,0) -10,0 cw(c0,0) 10,0 cw(c-0.25,0) -10.5,0 cw(c0,0) 10.5,0 cw(c-0.25,0) -11,0 cw(c0,0) 11,0 cw(c-0.25,0) -11.5,0 cw(c0,0) 11.5,0 cw(c-0.25,0) -12,0 cw(c0,0) 12,0 cw(c-0.25,0) -12.5,0 cw(c0,0) 12.5,0 cw(c-0.25,0) -13,0 cw(c0,0) 13,0 cw(c-0.25,0) -13.5,0 cw(c0,0) 13.5,0 cw(c-0.25,0) -14,0 cw(c0,0) 14,0 cw(c-0.25,0) -14.5,0 cw(c0,0) 14.5,0 cw(c-0.25,0) -15,0 cw(c0,0) 14.92,1.543 14.964,1.5 18.5,1.5 19.5,2.5
  lines w1: 15.726,2.949 ccw(c0,0) 16,0 19.5,0
Bottom Layer:
  region: 183 vertices and 0 holes, not listed, extent -16.508,-16.512 16.5,16.507
  region: 0,0 2,-2 2.5,-2 3.5,-1 15,-1 16,0 16,-0.61 15.907,-1.827 15.722,-3.033 15.445,-4.221 15.079,-5.385 14.625,-6.518 14.086,-7.612 13.466,-8.663 12.767,-9.663 11.994,-10.607 11.151,-11.49 10.244,-12.306 9.277,-13.05 8.257,-13.719 7.188,-14.307 6.078,-14.813 4.932,-15.233 3.758,-15.564 2.562,-15.805 1.351,-15.955 0.132,-16.011 -1.088,-15.975 -2.301,-15.845 -3.501,-15.624 -4.681,-15.312 -5.833,-14.911 -6.952,-14.424 -8.03,-13.853 -9.061,-13.201 -10.04,-12.473 -10.961,-11.672 -11.818,-10.803 -12.606,-9.872 -13.321,-8.883 -13.959,-7.843 -14.516,-6.757 -14.988,-5.632 -15.374,-4.475 -15.67,-3.291 -15.875,-2.088 -15.988,-0.873 -16.008,0.347 -15.935,1.565 -15.77,2.774 -15.513,3.966 -15.165,5.136 -14.73,6.276 -14.21,7.38 -13.606,8.44 -12.924,9.452 -12.167,10.409 -11.339,11.305 -10.445,12.135 -9.491,12.896 -8.481,13.581 -7.422,14.187 -6.321,14.711 -5.182,15.15 -4.013,15.501 -2.821,15.761 -1.613,15.93 -0.395,16.007 0.825,15.99 2.04,15.881 3.244,15.68 4.428,15.387 5.587,15.005 6.713,14.536 7.801,13.983 8.843,13.348 9.834,12.636 10.767,11.85 11.639,10.996 12.442,10.078 13.173,9.101 13.828,8.072 14.403,6.995 14.894,5.878 15.298,4.727 15.614,3.548 15.726,2.949 13.777,1 3.5,1 2.5,2 2,2
  lines w0.8: 2.35,-0.938 3.287,0 14.5,0 19.5,5
  lines w1: -1,0 0,-1 ; 19.5,0 16,0 ; 16,0 cw(c0,0) 15.726,2.949 13.777,1 3.75,1 2.75,2 2,2 0,0 2,-2 2.75,-2 3.75,-1 15,-1 16,0

## TRANS-1:4-SHIELD [mm] "PCB trace transformer, 1:4, shielded, 1A, 1µH, 500mOhm"
pads (5):
  round 2 hole 1: 1(19.5,-5) 2(19.5,-2.5) 3(19.5,2.5) 4(19.5,5) 5(19.5,0)
via 2.35,-0.938 diameter 0.4 hole 0.2
via 2.346,0.949 diameter 0.4 hole 0.2
via 16,0 diameter 0.4 hole 0.2
via 15.726,2.949 diameter 0.4 hole 0.2
via -16,0 diameter 0.4 hole 0.2
via 15.726,-2.949 diameter 0.4 hole 0.2
via 14.856,5.942 diameter 0.4 hole 0.2
via 14.856,-5.942 diameter 0.4 hole 0.2
via -5.5,15 diameter 0.4 hole 0.2
via -5.5,-15 diameter 0.4 hole 0.2
via -0.5,16 diameter 0.4 hole 0.2
via -0.5,-16 diameter 0.4 hole 0.2
via 14,-7.5 diameter 0.4 hole 0.2
via 14,7.5 diameter 0.4 hole 0.2
via 12.5,10 diameter 0.4 hole 0.2
via 12.5,-10 diameter 0.4 hole 0.2
via 10,-12.5 diameter 0.4 hole 0.2
via 10,12.5 diameter 0.4 hole 0.2
via 7.5,14 diameter 0.4 hole 0.2
via 7.5,-14 diameter 0.4 hole 0.2
via 5,15 diameter 0.4 hole 0.2
via 2,16 diameter 0.4 hole 0.2
via -3,16 diameter 0.4 hole 0.2
via 5,-15 diameter 0.4 hole 0.2
via -8,-14 diameter 0.4 hole 0.2
via -8,14 diameter 0.4 hole 0.2
via -10,12.5 diameter 0.4 hole 0.2
via -10,-12.5 diameter 0.4 hole 0.2
via -12,-10.5 diameter 0.4 hole 0.2
via -12,10.5 diameter 0.4 hole 0.2
via -14,8 diameter 0.4 hole 0.2
via -14,-8 diameter 0.4 hole 0.2
via -15,-5.5 diameter 0.4 hole 0.2
via -15,5.5 diameter 0.4 hole 0.2
via -16,2.5 diameter 0.4 hole 0.2
via -16,-2.5 diameter 0.4 hole 0.2
via 0,0 diameter 3.5 hole 3.5
via 2,-16 diameter 0.4 hole 0.2
via -3,-16 diameter 0.4 hole 0.2
Top Layer:
  region: 0,0 2,-2 2.5,-2 3.5,-1 13.777,-1 15.726,-2.949 15.614,-3.548 15.298,-4.727 14.894,-5.878 14.403,-6.995 13.828,-8.072 13.173,-9.101 12.442,-10.078 11.639,-10.996 10.767,-11.85 9.834,-12.636 8.843,-13.348 7.801,-13.983 6.713,-14.536 5.587,-15.005 4.428,-15.387 3.244,-15.68 2.04,-15.881 0.825,-15.99 -0.395,-16.007 -1.613,-15.93 -2.821,-15.761 -4.013,-15.501 -5.182,-15.15 -6.321,-14.711 -7.422,-14.187 -8.481,-13.581 -9.491,-12.896 -10.445,-12.135 -11.339,-11.305 -12.167,-10.409 -12.924,-9.452 -13.606,-8.44 -14.21,-7.38 -14.73,-6.276 -15.165,-5.136 -15.513,-3.966 -15.77,-2.774 -15.935,-1.565 -16.008,-0.347 -15.988,0.873 -15.875,2.088 -15.67,3.291 -15.374,4.475 -14.988,5.632 -14.516,6.757 -13.959,7.843 -13.321,8.883 -12.606,9.872 -11.818,10.803 -10.961,11.672 -10.04,12.473 -9.061,13.201 -8.03,13.853 -6.952,14.424 -5.833,14.911 -4.681,15.312 -3.501,15.624 -2.301,15.845 -1.088,15.975 0.132,16.011 1.351,15.955 2.562,15.805 3.758,15.564 4.932,15.233 6.078,14.813 7.188,14.307 8.257,13.719 9.277,13.05 10.244,12.306 11.151,11.49 11.994,10.607 12.767,9.663 13.466,8.663 14.086,7.612 14.625,6.518 15.079,5.385 15.445,4.221 15.722,3.033 15.907,1.827 16,0.61 16,0 15,1 3.5,1 2.5,2 2,2
  lines w0.254: 0,-1 1,-1
  lines w0.8: 2.346,0.949 3.295,0 14.5,0 19.5,-5
  lines w1: -1,0 0,1 ; 19.5,0 16,0 ; 16,0 ccw(c0,0) 15.726,-2.949 13.777,-1 3.75,-1 2.75,-2 2,-2 0,0 2,2 2.75,2 3.75,1 15,1 16,0
  text "Gravure en 0.15mm" at 15.5,-9.5 h1.52
Mid-Layer 1:
  lines w0.8: 2.346,0.949 ccw(c-0.5,0) -3.5,0 ccw(c0,0) 3.5,0 ccw(c-0.5,0) -4.5,0 ccw(c0,0) 4.5,0 ccw(c-0.5,0) -5.5,0 ccw(c0,0) 5.5,0 ccw(c-0.5,0) -6.5,0 ccw(c0,0) 6.5,0 ccw(c-0.5,0) -7.5,0 ccw(c0,0) 7.5,0 ccw(c-0.5,0) -8.5,0 ccw(c0,0) 8.5,0 ccw(c-0.5,0) -9.5,0 ccw(c0,0) 9.5,0 ccw(c-0.5,0) -10.5,0 ccw(c0,0) 10.5,0 ccw(c-0.5,0) -11.5,0 ccw(c0,0) 11.5,0 ccw(c-0.5,0) -12.5,0 ccw(c0,0) 12.5,0 ccw(c-0.5,0) -13.5,0 ccw(c0,0) 13.5,0 ccw(c-0.5,0) -14.5,0 ccw(c0,0) 14.423,-1.492 ; 14.5,-1.5 18.5,-1.5 19.5,-2.5
  lines w1: 15.726,-2.949 cw(c0,0) 16,0 19.5,0
Mid-Layer 2:
  lines w0.1: -14.251,0 cw(c0,0) 14.251,0 ; -14.25,0 ccw(c-0.125,0) 14,0 ccw(c0,0) -14,0 ccw(c-0.125,0) 13.75,0 ccw(c0,0) -13.75,0 ccw(c-0.125,0) 13.5,0 ccw(c0,0) -13.5,0 ccw(c-0.125,0) 13.25,0 ccw(c0,0) -13.25,0 ccw(c-0.125,0) 13,0 ccw(c0,0) -13,0 ccw(c-0.125,0) 12.75,0 ccw(c0,0) -12.75,0 ccw(c-0.125,0) 12.5,0 ccw(c0,0) -12.5,0 ccw(c-0.125,0) 12.25,0 ccw(c0,0) -12.25,0 ccw(c-0.125,0) 12,0 ccw(c0,0) -12,0 ccw(c-0.125,0) 11.75,0 ccw(c0,0) -11.75,0 ccw(c-0.125,0) 11.5,0 ccw(c0,0) -11.5,0 ccw(c-0.125,0) 11.25,0 ccw(c0,0) -11.25,0 ccw(c-0.125,0) 11,0 ccw(c0,0) -11,0 ccw(c-0.125,0) 10.75,0 ccw(c0,0) -10.75,0 ccw(c-0.125,0) 10.5,0 ccw(c0,0) -10.5,0 ccw(c-0.125,0) 10.25,0 ccw(c0,0) -10.25,0 ccw(c-0.125,0) 10,0 ccw(c0,0) -10,0 ccw(c-0.125,0) 9.75,0 ccw(c0,0) -9.75,0 ccw(c-0.125,0) 9.5,0 ccw(c0,0) -9.5,0 ccw(c-0.125,0) 9.25,0 ccw(c0,0) -9.25,0 ccw(c-0.125,0) 9,0 ccw(c0,0) -9,0 ccw(c-0.125,0) 8.75,0 ccw(c0,0) -8.75,0 ccw(c-0.125,0) 8.5,0 ccw(c0,0) -8.5,0 ccw(c-0.125,0) 8.25,0 ccw(c0,0) -8.25,0 ccw(c-0.125,0) 8,0 ccw(c0,0) -8,0 ccw(c-0.125,0) 7.75,0 ccw(c0,0) -7.75,0 ccw(c-0.125,0) 7.5,0 ccw(c0,0) -7.5,0 ccw(c-0.125,0) 7.25,0 ccw(c0,0) -7.25,0 ccw(c-0.125,0) 7,0 ccw(c0,0) -7,0 ccw(c-0.125,0) 6.75,0 ccw(c0,0) -6.75,0 ccw(c-0.125,0) 6.5,0 ccw(c0,0) -6.5,0 ccw(c-0.125,0) 6.25,0 ccw(c0,0) -6.25,0 ccw(c-0.125,0) 6,0 ccw(c0,0) -6,0 ccw(c-0.125,0) 5.75,0 ccw(c0,0) -5.75,0 ccw(c-0.125,0) 5.5,0 ccw(c0,0) -5.5,0 ccw(c-0.125,0) 5.25,0 ccw(c0,0) -5.25,0 ccw(c-0.125,0) 5,0 ccw(c0,0) -5,0 ccw(c-0.125,0) 4.75,0 ccw(c0,0) -4.75,0 ccw(c-0.125,0) 4.5,0 ccw(c0,0) -4.5,0 ccw(c-0.125,0) 4.25,0 ccw(c0,0) -4.25,0 ccw(c-0.125,0) 4,0 ccw(c0,0) -4,0 ccw(c-0.125,0) 3.75,0 ccw(c0,0) -3.75,0 ccw(c-0.125,0) 3.5,0 ccw(c0,0) -3.5,0 ccw(c-0.5,0) 2.35,-0.938 ; 14.25,0 cw(c-0.125,0) -14.5,0 cw(c0,0) 14.5,0 cw(c-0.125,0) -14.75,0 cw(c0,0) 14.75,0 cw(c-0.125,0) -15,0 cw(c0,0) 15,0 cw(c-0.125,0) -15.25,0 cw(c0,0) 15.169,1.569 15.238,1.5 18.5,1.5 19.5,2.5
  lines w1: 15.726,2.949 ccw(c0,0) 16,0 19.5,0
Bottom Layer:
  region: 183 vertices and 0 holes, not listed, extent -16.508,-16.512 16.5,16.507
  region: 0,0 2,-2 2.5,-2 3.5,-1 15,-1 16,0 16,-0.61 15.907,-1.827 15.722,-3.033 15.445,-4.221 15.079,-5.385 14.625,-6.518 14.086,-7.612 13.466,-8.663 12.767,-9.663 11.994,-10.607 11.151,-11.49 10.244,-12.306 9.277,-13.05 8.257,-13.719 7.188,-14.307 6.078,-14.813 4.932,-15.233 3.758,-15.564 2.562,-15.805 1.351,-15.955 0.132,-16.011 -1.088,-15.975 -2.301,-15.845 -3.501,-15.624 -4.681,-15.312 -5.833,-14.911 -6.952,-14.424 -8.03,-13.853 -9.061,-13.201 -10.04,-12.473 -10.961,-11.672 -11.818,-10.803 -12.606,-9.872 -13.321,-8.883 -13.959,-7.843 -14.516,-6.757 -14.988,-5.632 -15.374,-4.475 -15.67,-3.291 -15.875,-2.088 -15.988,-0.873 -16.008,0.347 -15.935,1.565 -15.77,2.774 -15.513,3.966 -15.165,5.136 -14.73,6.276 -14.21,7.38 -13.606,8.44 -12.924,9.452 -12.167,10.409 -11.339,11.305 -10.445,12.135 -9.491,12.896 -8.481,13.581 -7.422,14.187 -6.321,14.711 -5.182,15.15 -4.013,15.501 -2.821,15.761 -1.613,15.93 -0.395,16.007 0.825,15.99 2.04,15.881 3.244,15.68 4.428,15.387 5.587,15.005 6.713,14.536 7.801,13.983 8.843,13.348 9.834,12.636 10.767,11.85 11.639,10.996 12.442,10.078 13.173,9.101 13.828,8.072 14.403,6.995 14.894,5.878 15.298,4.727 15.614,3.548 15.726,2.949 13.777,1 3.5,1 2.5,2 2,2
  lines w0.8: 2.35,-0.938 3.287,0 14.5,0 19.5,5
  lines w1: -1,0 0,-1 ; 19.5,0 16,0 ; 16,0 cw(c0,0) 15.726,2.949 13.777,1 3.75,1 2.75,2 2,2 0,0 2,-2 2.75,-2 3.75,-1 15,-1 16,0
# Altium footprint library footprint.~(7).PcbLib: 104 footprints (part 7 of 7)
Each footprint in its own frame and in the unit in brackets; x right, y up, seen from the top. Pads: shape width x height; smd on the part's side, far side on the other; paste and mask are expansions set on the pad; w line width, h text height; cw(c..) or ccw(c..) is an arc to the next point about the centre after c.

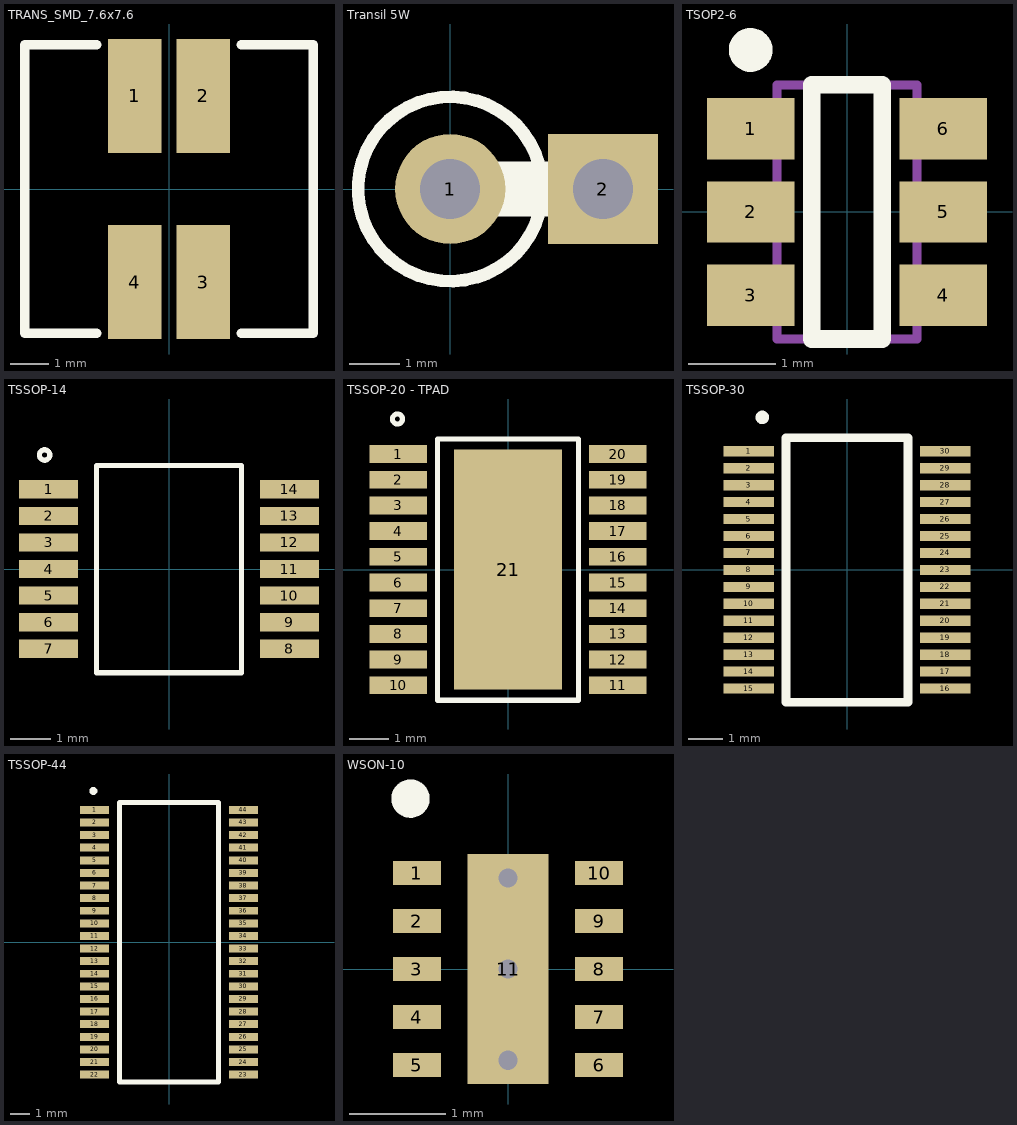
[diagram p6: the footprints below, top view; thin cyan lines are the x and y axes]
## TRANS_SMD_7.6x7.6 [mm] "Transfo SMD 7.6x7.6mm"
height 3.4
pads (4):
  rect 1.4x3 smd: 1(-0.9,2.45) 2(0.9,2.45) 3(0.9,-2.45) 4(-0.9,-2.45)
Top Overlay:
  lines w0.254: -1.9,-3.8 -3.8,-3.8 -3.8,3.8 -1.9,3.8 ; 1.9,-3.8 3.8,-3.8 3.8,3.8 1.9,3.8
3D body: height 3.4, standoff 0, extent -2.5,-2.497 2.5,2.497
3D body: height 3.35, standoff 0, extent -3.8,-3.8 3.8,3.8

## Transil 5W [mm] "diode transil 5W"
height 10
pads (2):
  round 2.2 hole 1.2: 1(0,0)
  rect 2.2x2.2 hole 1.2: 2(3.048,0)
Top Overlay:
  circle w0.254: c0,0 r1.84
  lines w1.1: 0,0 3.048,0

## TSOP2-6 [mm] "TSOP, 6-Leads, Body 2,90x1,60mm, Pitch 0,95mm, IPC Medium Density"
height 1
pads (6):
  rect 1x0.7 smd: 1(-1.099,0.95) 2(-1.099,0) 3(-1.099,-0.95) 4(1.099,-0.95) 5(1.099,0) 6(1.099,0.95)
Top Overlay:
  circle w0.25: c-1.099,1.85 r0.125
  lines w0.2: -0.4,-1.45 0.4,-1.45 0.4,1.45 -0.4,1.45 -0.4,-1.45
Mechanical 13:
  lines w0.1: -0.8,-1.45 0.8,-1.45 0.8,1.45 -0.8,1.45 -0.8,-1.45
3D body: height 1, standoff 0.01, extent -0.8,-1.45 0.8,1.45

## TSSOP-14 [mm]
height 1.2
pads (14):
  rect 1.45x0.45 smd: 1(-2.95,1.95) 2(-2.95,1.3) 3(-2.95,0.65) 4(-2.95,0) 5(-2.95,-0.65) 6(-2.95,-1.3) 7(-2.95,-1.95) 8(2.95,-1.95) 9(2.95,-1.3) 10(2.95,-0.65) 11(2.95,0) 12(2.95,0.65) 13(2.95,1.3) 14(2.95,1.95)
Top Overlay:
  circle w0.127: c-3.048,2.794 r0.127
  lines w0.127: -1.778,-2.54 -1.778,2.54 1.778,2.54 1.778,-2.54 -1.778,-2.54
3D body: height 1.2, standoff 0, extent -2.25,-2.55 2.25,2.55

## TSSOP-20 - TPAD [mm]
height 1.2
pads (21):
  rect 1.45x0.45 smd: 1(-2.775,2.925) 2(-2.775,2.275) 3(-2.775,1.625) 4(-2.775,0.975) 5(-2.775,0.325) 6(-2.775,-0.325) 7(-2.775,-0.975) 8(-2.775,-1.625) 9(-2.775,-2.275) 10(-2.775,-2.925) 11(2.775,-2.925) 12(2.775,-2.275) 13(2.775,-1.625) 14(2.775,-0.975) 15(2.775,-0.325) 16(2.775,0.325) 17(2.775,0.975) 18(2.775,1.625) 19(2.775,2.275) 20(2.775,2.925)
  rect 2.74x6.07 smd: 21(0,0)
Top Overlay:
  circle w0.127: c-2.794,3.81 r0.127
  lines w0.127: -1.778,-3.302 -1.778,3.302 1.778,3.302 1.778,-3.302 -1.778,-3.302
3D body: height 1.2, standoff 0, extent -2.2,-3.25 2.2,3.25

## TSSOP-30 [mm]
height 1.2
pads (30):
  rect 1.5x0.3 smd: 1(-2.9,3.5) 2(-2.9,3) 3(-2.9,2.5) 4(-2.9,2) 5(-2.9,1.5) 6(-2.9,1) 7(-2.9,0.5) 8(-2.9,0) 9(-2.9,-0.5) 10(-2.9,-1) 11(-2.9,-1.5) 12(-2.9,-2) 13(-2.9,-2.5) 14(-2.9,-3) 15(-2.9,-3.5) 16(2.9,-3.5) 17(2.9,-3) 18(2.9,-2.5) 19(2.9,-2) 20(2.9,-1.5) 21(2.9,-1) 22(2.9,-0.5) 23(2.9,0) 24(2.9,0.5) 25(2.9,1) 26(2.9,1.5) 27(2.9,2) 28(2.9,2.5) 29(2.9,3) 30(2.9,3.5)
Top Overlay:
  circle w0.2: c-2.5,4.5 r0.1
  lines w0.254: -1.8,-3.9 -1.8,3.9 1.8,3.9 1.8,-3.9 -1.8,-3.9
3D body: height 1, standoff 0.1, extent -2.2,-3.9 2.2,3.9

## TSSOP-44 [mm]
height 1.2
pads (44):
  rect 1.45x0.4 smd: 1(-3.75,6.667) 2(-3.75,6.032) 3(-3.75,5.397) 4(-3.75,4.763) 5(-3.75,4.127) 6(-3.75,3.492) 7(-3.75,2.857) 8(-3.75,2.222) 9(-3.75,1.587) 10(-3.75,0.953) 11(-3.75,0.318) 12(-3.75,-0.318) 13(-3.75,-0.953) 14(-3.75,-1.587) 15(-3.75,-2.222) 16(-3.75,-2.857) 17(-3.75,-3.492) 18(-3.75,-4.127) 19(-3.75,-4.763) 20(-3.75,-5.397) 21(-3.75,-6.032) 22(-3.75,-6.667) 23(3.75,-6.667) 24(3.75,-6.032) 25(3.75,-5.397) 26(3.75,-4.763) 27(3.75,-4.127) 28(3.75,-3.492) 29(3.75,-2.857) 30(3.75,-2.222) 31(3.75,-1.587) 32(3.75,-0.953) 33(3.75,-0.318) 34(3.75,0.318) 35(3.75,0.953) 36(3.75,1.587) 37(3.75,2.222) 38(3.75,2.857) 39(3.75,3.492) 40(3.75,4.127) 41(3.75,4.763) 42(3.75,5.397) 43(3.75,6.032) 44(3.75,6.667)
Top Overlay:
  circle w0.2: c-3.81,7.62 r0.1
  lines w0.254: -2.5,-7.05 -2.5,7.05 2.5,7.05 2.5,-7.05 -2.5,-7.05
3D body: height 1, standoff 0.1, extent -3.1,-7.05 3.1,7.05

## WSON-10 [mm] "QFN10 + termal pad"
height 0.8
pads (11):
  rect 0.5x0.25 smd: 1(-0.95,1) 2(-0.95,0.5) 3(-0.95,0) 4(-0.95,-0.5) 5(-0.95,-1) 6(0.95,-1) 7(0.95,-0.5) 8(0.95,0) 9(0.95,0.5) 10(0.95,1)
  rect 0.84x2.4 smd: 11(0,0)
via 0,-0.95 diameter 0.4 hole 0.2
via 0,0.95 diameter 0.4 hole 0.2
via 0,0 diameter 0.4 hole 0.2
Top Overlay:
  circle w0.2: c-1.016,1.778 r0.1
3D body: height 0.8, standoff 0, extent -1,-1.5 1,1.5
